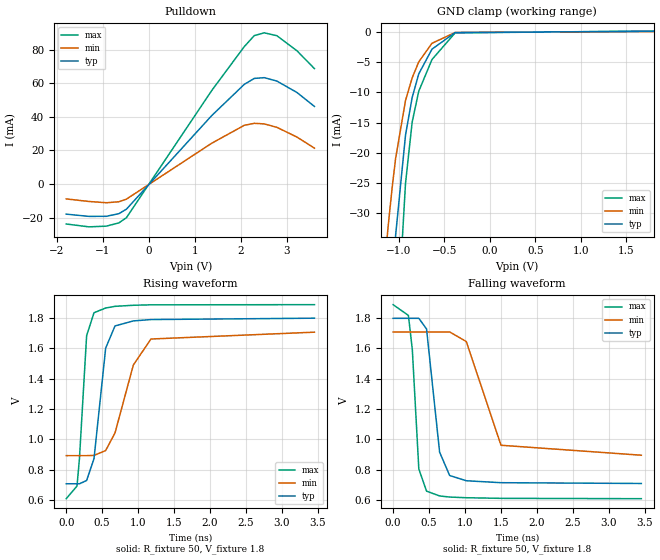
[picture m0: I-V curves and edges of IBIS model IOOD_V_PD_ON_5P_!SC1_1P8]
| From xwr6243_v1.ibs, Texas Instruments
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|   Model Cell IOOD_V_PD_ON_5P_!SC1_1P8
|IOOD_V_PD_ON_5P_!SC1_1P8
[Model]   IOOD_V_PD_ON_5P_!SC1_1P8
Model_type   I/O_open_drain
Polarity   Non-Inverting
Enable   Active-Low
Vinl =  0.63
Vinh =  1.17
Cref =  15pF
Rref =  100.0000M
Vref =  0V
Vmeas =  0.9
|   typ   min   max
C_comp   2.233931p   2.204415p   2.290246p
[Model Spec]
Vinl   0.63   0.5985   0.6615
Vinh   1.17   1.1115   1.2285
[Temperature Range]   25   125   -40
[Voltage Range]   1.8   1.71   1.89
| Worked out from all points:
|   slope of the pulldown table from 0 to 0.27 V, typ, clamps not added: 32.2 ohm
|   GND clamp passes 1 mA (typ) near -0.53 V on its own axis
|   rising waveform, R_fixture 50, V_fixture 1.8: 20-80 % time 141ps typ, 294ps min, 91.5ps max; typ from 0.708 V to 1.8 V
|   falling waveform, R_fixture 50, V_fixture 1.8: 20-80 % time 128ps typ, 263ps min, 86.2ps max; typ from 1.8 V to 0.709 V
| Where Nom  PVT is Nominal Process, 1.8V, 25C
|   Fast PVT is Strong Process,  1.89V, -40C
|   Slow PVT is Weak Process,   1.71V, 125C
[Pulldown]
|   voltage   I(typ)   I(min)   I(max)
-1.8V     -17.92mA   -8.85mA    -23.8mA
-1.309V   -19.26mA   -10.37mA   -25.5mA
-927.3mV  -19.22mA   -11.12mA   -25.08mA
-654.5mV  -17.65mA   -10.56mA   -23.13mA
-490.9mV  -14.97mA   -8.985mA   -20.05mA
1.364V    40.78mA    24.32mA    55.69mA
2.073V    59.4mA     35mA       81.9mA
2.291V    62.96mA    36.2mA     88.48mA
2.509V    63.41mA    35.84mA    90.12mA
2.782V    61.38mA    33.82mA    88.42mA
3.218V    54.59mA    28.02mA    79.45mA
3.6V      46.26mA    21.39mA    68.79mA
[GND_clamp]
|   voltage   I(typ)   I(min)   I(max)
-1.8V     -270.2mA   -170.2mA   -430.1mA
-1.255V   -91.66mA   -55.91mA   -148.4mA
-1.145V   -59.91mA   -36.45mA   -97.1mA
-1.109V   -50.48mA   -30.83mA   -81.56mA
-1.073V   -41.73mA   -25.65mA   -67.06mA
-1.036V   -33.67mA   -20.93mA   -53.6mA
-927.3mV  -17.08mA   -11.35mA   -25.06mA
-854.5mV  -10.88mA   -7.624mA   -14.94mA
-781.8mV  -6.944mA   -4.956mA   -9.81mA
-636.4mV  -2.852mA   -1.883mA   -4.567mA
-381.8mV  -107.5uA   -92.09uA   -158.2uA
1.8V      101.9uA    59.12uA    150.8uA
[Ramp]
| variable   typ   min   max
dV/dt_f 0.66510514/0.13039257n 0.49951363/0.26900827n 0.77657515/87.836977p
dV/dt_r 0.66379743/0.17656601n 0.50939443/0.36426095n 0.78039524/0.10503855n
R_load = 50
[Rising Waveform]
R_fixture = 50
V_fixture = 1.8
V_fixture_min = 1.71
V_fixture_max = 1.89
|   time   V(typ)   V(min)   V(max)
0s        708.5mV    893.6mV    610.3mV
149.8ps   708.5mV    893.6mV    693.4mV
183.7ps   708.5mV    893.6mV    873.7mV
283.5ps   729.6mV    893.6mV    1.683V
386.4ps   874.1mV    894.9mV    1.834V
548.5ps   1.601V     927.1mV    1.865V
678.4ps   1.747V     1.043V     1.876V
933.5ps   1.78V      1.49V      1.883V
1.179ns   1.789V     1.661V     1.886V
3.453ns   1.798V     1.706V     1.887V
[Falling Waveform]
R_fixture = 50
V_fixture = 1.8
V_fixture_min = 1.71
V_fixture_max = 1.89
|   time   V(typ)   V(min)   V(max)
0s        1.798V     1.708V     1.888V
212.8ps   1.798V     1.708V     1.817V
267.2ps   1.798V     1.708V     1.592V
357.7ps   1.798V     1.708V     804.9mV
465ps     1.728V     1.708V     658.8mV
646.9ps   915.8mV    1.708V     627.2mV
786.7ps   761.8mV    1.708V     619.9mV
1.018ns   727.3mV    1.645V     615.4mV
1.501ns   714.5mV    961.2mV    611.3mV
3.453ns   709.3mV    895.6mV    609.1mV
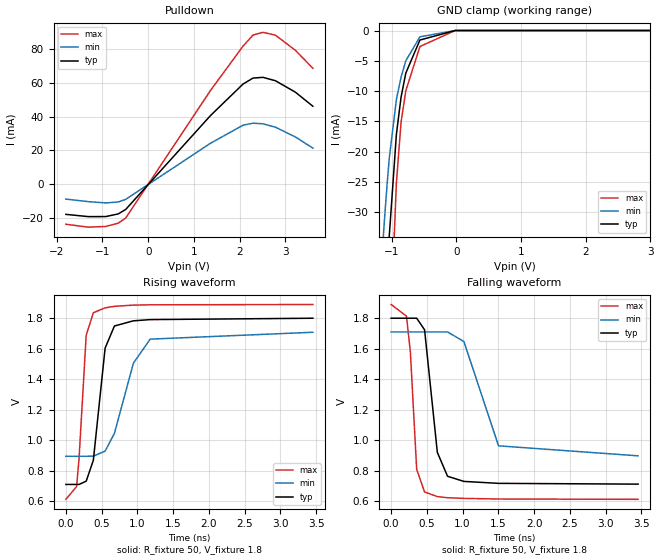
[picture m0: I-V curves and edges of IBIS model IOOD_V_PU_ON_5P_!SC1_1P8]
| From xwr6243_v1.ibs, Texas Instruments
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|   Model Cell IOOD_V_PU_ON_5P_!SC1_1P8
|IOOD_V_PU_ON_5P_!SC1_1P8
[Model]   IOOD_V_PU_ON_5P_!SC1_1P8
Model_type   I/O_open_drain
Polarity   Non-Inverting
Enable   Active-Low
Vinl =  0.63
Vinh =  1.17
Cref =  15pF
Rref =  100.0000M
Vref =  0V
Vmeas =  0.9
|   typ   min   max
C_comp   2.233931p   2.204415p   2.290246p
[Model Spec]
Vinl   0.63   0.5985   0.6615
Vinh   1.17   1.1115   1.2285
[Temperature Range]   25   125   -40
[Voltage Range]   1.8   1.71   1.89
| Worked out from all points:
|   slope of the pulldown table from 0 to 0.27 V, typ, clamps not added: 32.2 ohm
|   GND clamp passes 1 mA (typ) near -0.52 V on its own axis
|   rising waveform, R_fixture 50, V_fixture 1.8: 20-80 % time 141ps typ, 293ps min, 91.4ps max; typ from 0.711 V to 1.8 V
|   falling waveform, R_fixture 50, V_fixture 1.8: 20-80 % time 128ps typ, 263ps min, 86.1ps max; typ from 1.8 V to 0.711 V
| Where Nom  PVT is Nominal Process, 1.8V, 25C
|   Fast PVT is Strong Process,  1.89V, -40C
|   Slow PVT is Weak Process,   1.71V, 125C
[Pulldown]
|   voltage   I(typ)   I(min)   I(max)
-1.8V     -17.92mA   -8.85mA    -23.8mA
-1.309V   -19.26mA   -10.37mA   -25.51mA
-927.3mV  -19.22mA   -11.12mA   -25.08mA
-654.5mV  -17.65mA   -10.56mA   -23.13mA
-490.9mV  -14.97mA   -8.985mA   -20.05mA
1.364V    40.78mA    24.32mA    55.7mA
2.073V    59.41mA    35mA       81.9mA
2.291V    62.96mA    36.2mA     88.48mA
2.509V    63.41mA    35.84mA    90.12mA
2.782V    61.38mA    33.82mA    88.42mA
3.218V    54.59mA    28.02mA    79.45mA
3.6V      46.26mA    21.39mA    68.79mA
[GND_clamp]
|   voltage   I(typ)   I(min)   I(max)
-1.8V     -270.2mA   -170.2mA   -430.1mA
-1.255V   -91.68mA   -55.92mA   -148.5mA
-1.145V   -59.94mA   -36.46mA   -97.14mA
-1.109V   -50.51mA   -30.84mA   -81.61mA
-1.073V   -41.77mA   -25.67mA   -67.13mA
-1.036V   -33.71mA   -20.95mA   -53.68mA
-927.3mV  -17.15mA   -11.38mA   -25.19mA
-854.5mV  -10.96mA   -7.663mA   -15.08mA
-781.8mV  -7.031mA   -5.001mA   -9.947mA
-563.6mV  -1.569mA   -1.041mA   -2.641mA
-18.18mV  0A         0A         0A
3.6V      0A         0A         0A
[Ramp]
| variable   typ   min   max
dV/dt_f 0.66507934/0.13047563n 0.49947306/0.26909371n 0.77654614/87.861951p
dV/dt_r 0.66370141/0.17654672n 0.50912868/0.36419589n 0.78039356/0.10498627n
R_load = 50
[Rising Waveform]
R_fixture = 50
V_fixture = 1.8
V_fixture_min = 1.71
V_fixture_max = 1.89
|   time   V(typ)   V(min)   V(max)
0s        710.6mV    895.2mV    613mV
149.8ps   710.6mV    895.2mV    696.6mV
183.7ps   710.6mV    895.2mV    877.5mV
284.2ps   732.1mV    895.2mV    1.689V
384.1ps   869.5mV    896.4mV    1.836V
548.5ps   1.604V     928.8mV    1.868V
678.4ps   1.749V     1.045V     1.878V
943.6ps   1.783V     1.505V     1.886V
1.179ns   1.791V     1.663V     1.888V
3.453ns   1.8V       1.708V     1.89V
[Falling Waveform]
R_fixture = 50
V_fixture = 1.8
V_fixture_min = 1.71
V_fixture_max = 1.89
|   time   V(typ)   V(min)   V(max)
0s        1.8V       1.71V      1.89V
215ps     1.8V       1.71V      1.814V
269.6ps   1.8V       1.71V      1.578V
357.6ps   1.8V       1.71V      808.4mV
468ps     1.724V     1.71V      660.2mV
646.5ps   919.7mV    1.71V      629.7mV
789.1ps   763.1mV    1.71V      622.3mV
1.018ns   729.3mV    1.647V     617.9mV
1.502ns   716.5mV    962.7mV    613.8mV
3.453ns   711.4mV    897.1mV    611.7mV
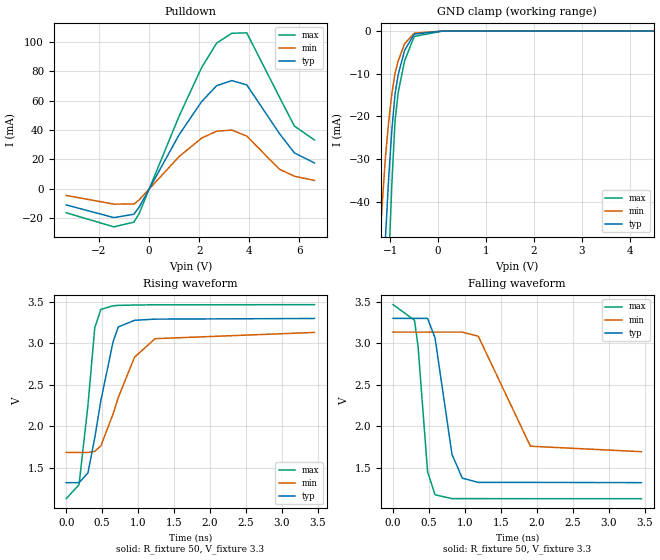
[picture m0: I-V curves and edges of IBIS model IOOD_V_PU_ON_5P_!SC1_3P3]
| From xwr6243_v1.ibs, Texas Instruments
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|   Model Cell IOOD_V_PU_ON_5P_!SC1_3P3
|IOOD_V_PU_ON_5P_!SC1_3P3
[Model]   IOOD_V_PU_ON_5P_!SC1_3P3
Model_type   I/O_open_drain
Polarity   Non-Inverting
Enable   Active-Low
Vinl =  0.8V
Vinh =  2V
Cref =  15pF
Rref =  100.0000M
Vref =  0V
Vmeas =  1.65
|   typ   min   max
C_comp   2.059994p   1.862014p   2.067327p
[Model Spec]
Vinl   0.8V   0.8V   0.8V
Vinh   2V   2V   2V
[Temperature Range]   25   125   -40
[Voltage Range]   3.3   3.135   3.465
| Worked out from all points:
|   slope of the pulldown table from 0 to 0.495 V, typ, clamps not added: 31.8 ohm
|   GND clamp passes 1 mA (typ) near -0.52 V on its own axis
|   rising waveform, R_fixture 50, V_fixture 3.3: 20-80 % time 251ps typ, 370ps min, 151ps max; typ from 1.32 V to 3.3 V
|   falling waveform, R_fixture 50, V_fixture 3.3: 20-80 % time 196ps typ, 407ps min, 120ps max; typ from 3.3 V to 1.32 V
| Where Nom  PVT is Nominal Process, 3.3V, 25C
|   Fast PVT is Strong Process,  3.465V, -40C
|   Slow PVT is Weak Process,   3.135V, 125C
[Pulldown]
|   voltage   I(typ)   I(min)   I(max)
-3.3V     -10.92mA   -4.469mA   -16.24mA
-1.4V     -19.52mA   -10.37mA   -25.81mA
-600mV    -17.22mA   -10.34mA   -22.6mA
-400mV    -12.67mA   -7.623mA   -17.05mA
1.2V      36.7mA     21.92mA    49.35mA
2.1V      59.3mA     34.49mA    82.4mA
2.7V      70.09mA    39.15mA    99.03mA
3.3V      73.56mA    39.95mA    105.7mA
3.9V      70.66mA    35.84mA    106mA
5.2V      37.64mA    13.39mA    62.46mA
5.8V      24.43mA    8.578mA    42.66mA
6.6V      17.6mA     5.765mA    33.17mA
[GND_clamp]
|   voltage   I(typ)   I(min)   I(max)
-3.3V     -787.2mA   -627.7mA   -1.235A
-1.233V   -85.67mA   -52.14mA   -138.8mA
-1.167V   -66.48mA   -40.37mA   -107.8mA
-1.1V     -48.26mA   -29.38mA   -78.01mA
-1.033V   -34.3mA    -21.2mA    -54.61mA
-966.7mV  -23.1mA    -14.68mA   -35.59mA
-900mV    -14.66mA   -9.807mA   -20.94mA
-833.3mV  -10.12mA   -6.96mA    -14.29mA
-700mV    -4.501mA   -2.971mA   -6.963mA
-500mV    -717.7uA   -493.4uA   -1.261mA
100mV     0A         0A         0A
6.6V      0A         0A         0A
[Ramp]
| variable   typ   min   max
dV/dt_f  1.1950495/0.19765753n 0.88964479/0.4200289n  1.4061684/0.12033881n
dV/dt_r  1.1911245/0.23430808n 0.88879161/0.46777455n  1.4196341/0.14133941n
R_load = 50
[Rising Waveform]
R_fixture = 50
V_fixture = 3.3
V_fixture_min = 3.135
V_fixture_max = 3.465
|   time   V(typ)   V(min)   V(max)
0s        1.324V     1.688V     1.132V
178.2ps   1.325V     1.688V     1.3V
302ps     1.441V     1.688V     2.255V
397.2ps   1.866V     1.701V     3.188V
481.7ps   2.312V     1.767V     3.408V
652.6ps   3.023V     2.153V     3.452V
724.3ps   3.197V     2.349V     3.456V
949.9ps   3.277V     2.833V     3.461V
1.235ns   3.291V     3.056V     3.463V
3.453ns   3.299V     3.131V     3.465V
[Falling Waveform]
R_fixture = 50
V_fixture = 3.3
V_fixture_min = 3.135
V_fixture_max = 3.465
|   time   V(typ)   V(min)   V(max)
0s        3.299V     3.134V     3.464V
297.1ps   3.299V     3.134V     3.277V
347.5ps   3.299V     3.134V     2.96V
479.3ps   3.299V     3.134V     1.457V
583.2ps   3.064V     3.134V     1.178V
818.9ps   1.664V     3.134V     1.132V
962ps     1.378V     3.134V     1.132V
1.185ns   1.327V     3.084V     1.132V
1.91ns    1.327V     1.762V     1.131V
3.453ns   1.324V     1.696V     1.131V
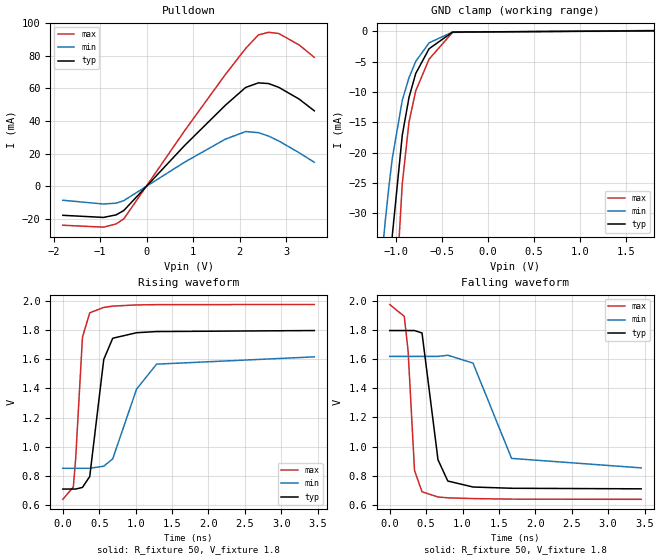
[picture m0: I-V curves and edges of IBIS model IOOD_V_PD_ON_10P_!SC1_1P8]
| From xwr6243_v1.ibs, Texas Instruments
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|   Model Cell IOOD_V_PD_ON_10P_!SC1_1P8
|IOOD_V_PD_ON_10P_!SC1_1P8
[Model]   IOOD_V_PD_ON_10P_!SC1_1P8
Model_type   I/O_open_drain
Polarity   Non-Inverting
Enable   Active-Low
Vinl =  0.63
Vinh =  1.17
Cref =  15pF
Rref =  100.0000M
Vref =  0V
Vmeas =  0.9
|   typ   min   max
C_comp   2.290246p   2.205796p   2.292736p
[Model Spec]
Vinl   0.63   0.567   0.693
Vinh   1.17   1.053   1.287
[Temperature Range]   25   125   -40
[Voltage Range]   1.8   1.62   1.98
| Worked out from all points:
|   slope of the pulldown table from 0 to 0.27 V, typ, clamps not added: 32.2 ohm
|   GND clamp passes 1 mA (typ) near -0.53 V on its own axis
|   rising waveform, R_fixture 50, V_fixture 1.8: 20-80 % time 141ps typ, 321ps min, 87.4ps max; typ from 0.709 V to 1.8 V
|   falling waveform, R_fixture 50, V_fixture 1.8: 20-80 % time 128ps typ, 291ps min, 84ps max; typ from 1.8 V to 0.709 V
| Where Nom  PVT is Nominal Process, 1.8V, 25C
|   Fast PVT is Strong Process,  1.98V, -40C
|   Slow PVT is Weak Process,   1.62V, 125C
[Pulldown]
|   voltage   I(typ)   I(min)   I(max)
-1.8V     -17.92mA   -8.674mA   -24.03mA
-927.3mV  -19.22mA   -10.99mA   -25.2mA
-654.5mV  -17.65mA   -10.46mA   -23.22mA
-490.9mV  -14.97mA   -8.904mA   -20.12mA
818.2mV   25.05mA    14.78mA    34.16mA
1.691V    49.7mA     28.87mA    68.58mA
2.127V    60.63mA    33.53mA    84.59mA
2.4V      63.43mA    32.85mA    92.9mA
2.618V    62.99mA    30.74mA    94.47mA
2.836V    60.69mA    27.76mA    93.76mA
3.273V    53.49mA    20.53mA    86.73mA
3.6V      46.26mA    14.64mA    79.12mA
[GND_clamp]
|   voltage   I(typ)   I(min)   I(max)
-1.8V     -270.2mA   -170.2mA   -430.1mA
-1.255V   -91.66mA   -55.91mA   -148.4mA
-1.145V   -59.91mA   -36.45mA   -97.1mA
-1.109V   -50.48mA   -30.83mA   -81.56mA
-1.073V   -41.73mA   -25.65mA   -67.06mA
-1.036V   -33.67mA   -20.93mA   -53.6mA
-927.3mV  -17.08mA   -11.35mA   -25.06mA
-854.5mV  -10.88mA   -7.623mA   -14.95mA
-781.8mV  -6.944mA   -4.955mA   -9.81mA
-636.4mV  -2.852mA   -1.883mA   -4.568mA
-381.8mV  -107.5uA   -91.83uA   -158.4uA
1.8V      101.9uA    59.86uA    152.6uA
[Ramp]
| variable   typ   min   max
dV/dt_f 0.66510519/0.13032151n 0.47058165/0.29690499n 0.81401058/85.695381p
dV/dt_r 0.66379761/0.17655114n 0.48092033/0.39577716n 0.81801831/99.528337p
R_load = 50
[Rising Waveform]
R_fixture = 50
V_fixture = 1.8
V_fixture_min = 1.62
V_fixture_max = 1.98
|   time   V(typ)   V(min)   V(max)
0s        708.5mV    851.3mV    637.8mV
143.7ps   708.5mV    851.3mV    722.4mV
176.4ps   708.5mV    851.3mV    920mV
269.4ps   719.8mV    851.3mV    1.753V
369.4ps   794.8mV    851.3mV    1.92V
561.6ps   1.599V     865.5mV    1.957V
684.8ps   1.745V     916mV      1.966V
1.012ns   1.783V     1.395V     1.974V
1.287ns   1.791V     1.567V     1.976V
3.453ns   1.798V     1.617V     1.977V
[Falling Waveform]
R_fixture = 50
V_fixture = 1.8
V_fixture_min = 1.62
V_fixture_max = 1.98
|   time   V(typ)   V(min)   V(max)
0s        1.798V     1.62V      1.977V
200.1ps   1.798V     1.62V      1.895V
252.3ps   1.798V     1.62V      1.658V
340.4ps   1.798V     1.62V      835.7mV
443.5ps   1.781V     1.62V      689.1mV
663.1ps   908.8mV    1.62V      653.2mV
797.3ps   763mV      1.628V     647.2mV
1.144ns   721.8mV    1.574V     642.3mV
1.673ns   713.2mV    918.6mV    638.4mV
3.453ns   709.3mV    853.4mV    637.1mV
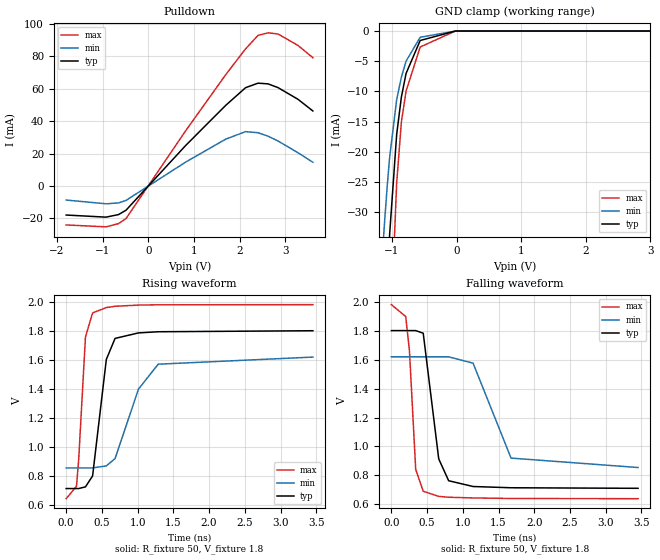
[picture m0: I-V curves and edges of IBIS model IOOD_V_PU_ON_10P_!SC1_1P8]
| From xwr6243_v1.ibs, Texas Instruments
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|   Model Cell IOOD_V_PU_ON_10P_!SC1_1P8
|IOOD_V_PU_ON_10P_!SC1_1P8
[Model]   IOOD_V_PU_ON_10P_!SC1_1P8
Model_type   I/O_open_drain
Polarity   Non-Inverting
Enable   Active-Low
Vinl =  0.63
Vinh =  1.17
Cref =  15pF
Rref =  100.0000M
Vref =  0V
Vmeas =  0.9
|   typ   min   max
C_comp   2.290246p   2.205796p   2.292736p
[Model Spec]
Vinl   0.63   0.567   0.693
Vinh   1.17   1.053   1.287
[Temperature Range]   25   125   -40
[Voltage Range]   1.8   1.62   1.98
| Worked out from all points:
|   slope of the pulldown table from 0 to 0.27 V, typ, clamps not added: 32.2 ohm
|   GND clamp passes 1 mA (typ) near -0.52 V on its own axis
|   rising waveform, R_fixture 50, V_fixture 1.8: 20-80 % time 141ps typ, 321ps min, 87.2ps max; typ from 0.71 V to 1.8 V
|   falling waveform, R_fixture 50, V_fixture 1.8: 20-80 % time 128ps typ, 290ps min, 84ps max; typ from 1.8 V to 0.711 V
| Where Nom  PVT is Nominal Process, 1.8V, 25C
|   Fast PVT is Strong Process,  1.98V, -40C
|   Slow PVT is Weak Process,   1.62V, 125C
[Pulldown]
|   voltage   I(typ)   I(min)   I(max)
-1.8V     -17.92mA   -8.674mA   -24.03mA
-927.3mV  -19.22mA   -10.99mA   -25.21mA
-654.5mV  -17.65mA   -10.46mA   -23.22mA
-490.9mV  -14.97mA   -8.904mA   -20.12mA
818.2mV   25.06mA    14.78mA    34.16mA
1.691V    49.7mA     28.87mA    68.59mA
2.127V    60.63mA    33.53mA    84.59mA
2.4V      63.43mA    32.84mA    92.9mA
2.618V    62.99mA    30.74mA    94.47mA
2.836V    60.69mA    27.76mA    93.76mA
3.273V    53.49mA    20.53mA    86.73mA
3.6V      46.26mA    14.64mA    79.11mA
[GND_clamp]
|   voltage   I(typ)   I(min)   I(max)
-1.8V     -270.2mA   -170.2mA   -430.1mA
-1.255V   -91.68mA   -55.92mA   -148.5mA
-1.145V   -59.94mA   -36.46mA   -97.15mA
-1.109V   -50.51mA   -30.84mA   -81.62mA
-1.073V   -41.77mA   -25.67mA   -67.14mA
-1.036V   -33.71mA   -20.94mA   -53.69mA
-927.3mV  -17.15mA   -11.38mA   -25.2mA
-854.5mV  -10.96mA   -7.657mA   -15.09mA
-781.8mV  -7.031mA   -4.995mA   -9.958mA
-563.6mV  -1.569mA   -1.036mA   -2.651mA
-18.18mV  0A         0A         0A
3.6V      0A         0A         0A
[Ramp]
| variable   typ   min   max
dV/dt_f  0.6650793/0.13041675n 0.47054236/0.29704481n 0.81398134/85.756989p
dV/dt_r 0.66369803/0.17655946n 0.48061665/0.39565974n 0.81803201/99.446129p
R_load = 50
[Rising Waveform]
R_fixture = 50
V_fixture = 1.8
V_fixture_min = 1.62
V_fixture_max = 1.98
|   time   V(typ)   V(min)   V(max)
0s        710.4mV    852.8mV    640.4mV
144.3ps   710.4mV    852.8mV    725.7mV
175.6ps   710.4mV    852.8mV    911.9mV
270.1ps   722mV      852.8mV    1.757V
370ps     797.4mV    852.8mV    1.923V
562.2ps   1.602V     867mV      1.96V
684.5ps   1.747V     917.1mV    1.969V
1.012ns   1.785V     1.397V     1.977V
1.288ns   1.793V     1.569V     1.979V
3.453ns   1.8V       1.618V     1.98V
[Falling Waveform]
R_fixture = 50
V_fixture = 1.8
V_fixture_min = 1.62
V_fixture_max = 1.98
|   time   V(typ)   V(min)   V(max)
0s        1.8V       1.619V     1.979V
200.7ps   1.8V       1.619V     1.897V
252.9ps   1.8V       1.619V     1.661V
340.6ps   1.8V       1.619V     841.1mV
445.7ps   1.782V     1.619V     691.1mV
662.6ps   914.6mV    1.619V     655.8mV
801.7ps   763.7mV    1.619V     649.7mV
1.144ns   723.8mV    1.575V     644.9mV
1.675ns   715.2mV    919.9mV    641.1mV
3.453ns   711.4mV    854.9mV    639.8mV
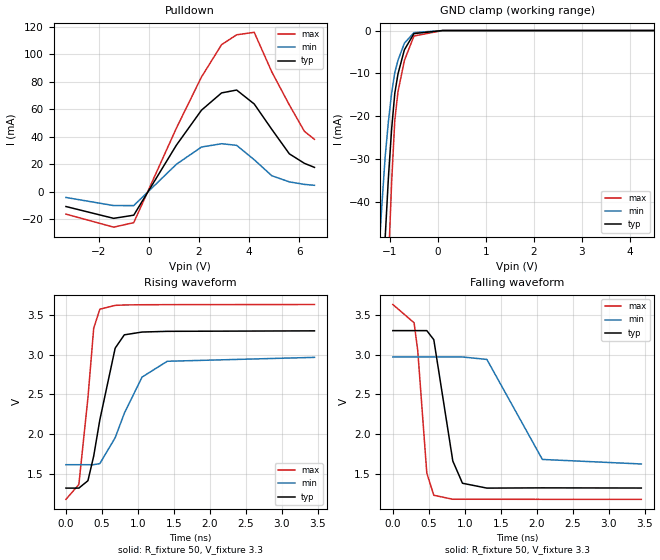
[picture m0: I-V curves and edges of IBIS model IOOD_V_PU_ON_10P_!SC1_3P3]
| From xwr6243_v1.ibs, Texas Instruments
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|   Model Cell IOOD_V_PU_ON_10P_!SC1_3P3
|IOOD_V_PU_ON_10P_!SC1_3P3
[Model]   IOOD_V_PU_ON_10P_!SC1_3P3
Model_type   I/O_open_drain
Polarity   Non-Inverting
Enable   Active-Low
Vinl =  0.8V
Vinh =  2V
Cref =  15pF
Rref =  100.0000M
Vref =  0V
Vmeas =  1.65
|   typ   min   max
C_comp   2.059994p   1.912853p   2.135747p
[Model Spec]
Vinl   0.8V   0.8V   0.8V
Vinh   2V   2V   2V
[Temperature Range]   25   125   -40
[Voltage Range]   3.3   2.97   3.63
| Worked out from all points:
|   slope of the pulldown table from 0 to 0.495 V, typ, clamps not added: 31.8 ohm
|   GND clamp passes 1 mA (typ) near -0.52 V on its own axis
|   rising waveform, R_fixture 50, V_fixture 3.3: 20-80 % time 251ps typ, 384ps min, 142ps max; typ from 1.32 V to 3.3 V
|   falling waveform, R_fixture 50, V_fixture 3.3: 20-80 % time 196ps typ, 423ps min, 118ps max; typ from 3.3 V to 1.32 V
| Where Nom  PVT is Nominal Process, 3.3V, 25C
|   Fast PVT is Strong Process,  3.63V, -40C
|   Slow PVT is Weak Process,   2.97V, 125C
[Pulldown]
|   voltage   I(typ)   I(min)   I(max)
-3.3V     -10.92mA   -4.307mA   -16.45mA
-1.4V     -19.52mA   -10.22mA   -25.94mA
-600mV    -17.22mA   -10.25mA   -22.66mA
1.1V      33.8mA     19.88mA    46.22mA
2.1V      59.3mA     32.44mA    83.48mA
2.9V      71.86mA    34.84mA    107mA
3.5V      73.95mA    33.66mA    114.2mA
4.2V      63.8mA     23.19mA    116mA
4.9V      45.33mA    11.53mA    87.2mA
5.6V      27.47mA    7.046mA    63.1mA
6.2V      20.56mA    5.221mA    43.87mA
6.6V      17.6mA     4.555mA    38.05mA
[GND_clamp]
|   voltage   I(typ)   I(min)   I(max)
-3.3V     -787.2mA   -607.8mA   -1.235A
-1.233V   -85.67mA   -52.14mA   -138.8mA
-1.167V   -66.48mA   -40.37mA   -107.8mA
-1.1V     -48.26mA   -29.37mA   -78.02mA
-1.033V   -34.3mA    -21.2mA    -54.63mA
-966.7mV  -23.1mA    -14.67mA   -35.61mA
-900mV    -14.66mA   -9.802mA   -20.96mA
-833.3mV  -10.12mA   -6.954mA   -14.3mA
-700mV    -4.501mA   -2.964mA   -6.982mA
-500mV    -717.7uA   -486.4uA   -1.28mA
100mV     0A         0A         0A
6.6V      0A         0A         0A
[Ramp]
| variable   typ   min   max
dV/dt_f  1.1950496/0.19764937n 0.83550004/0.43952187n  1.4746494/0.11842933n
dV/dt_r  1.1911253/0.23433637n 0.82860168/0.48872151n  1.4896931/0.13693182n
R_load = 50
[Rising Waveform]
R_fixture = 50
V_fixture = 3.3
V_fixture_min = 2.97
V_fixture_max = 3.63
|   time   V(typ)   V(min)   V(max)
0s        1.324V     1.618V     1.183V
179.3ps   1.324V     1.618V     1.369V
305.5ps   1.417V     1.618V     2.459V
385.5ps   1.726V     1.618V     3.332V
470.7ps   2.181V     1.632V     3.571V
684ps     3.082V     1.957V     3.619V
810.8ps   3.249V     2.263V     3.624V
1.057ns   3.284V     2.718V     3.627V
1.408ns   3.293V     2.917V     3.628V
3.453ns   3.299V     2.966V     3.63V
[Falling Waveform]
R_fixture = 50
V_fixture = 3.3
V_fixture_min = 2.97
V_fixture_max = 3.63
|   time   V(typ)   V(min)   V(max)
0s        3.301V     2.97V      3.629V
295.6ps   3.301V     2.97V      3.399V
346.7ps   3.301V     2.97V      3.046V
472.1ps   3.301V     2.97V      1.511V
569.4ps   3.187V     2.97V      1.233V
833.3ps   1.664V     2.97V      1.183V
967.6ps   1.384V     2.97V      1.183V
1.307ns   1.323V     2.939V     1.183V
2.078ns   1.326V     1.683V     1.182V
3.453ns   1.324V     1.626V     1.182V
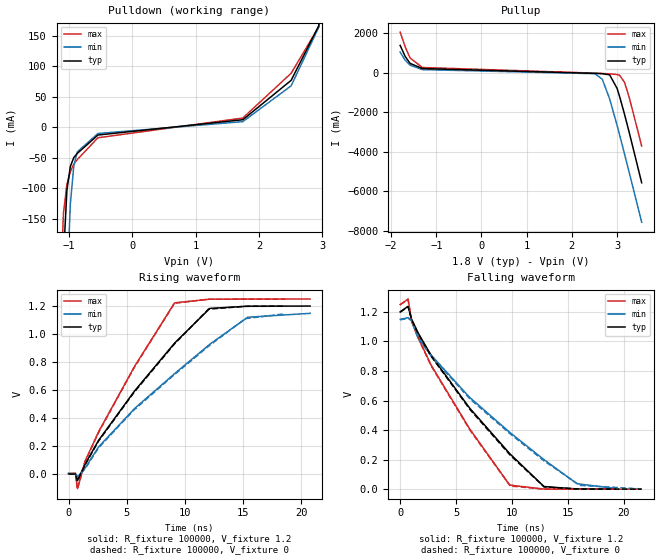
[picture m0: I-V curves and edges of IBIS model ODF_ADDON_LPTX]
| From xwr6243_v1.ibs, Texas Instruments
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|   Model Cell ODF_ADDON_LPTX
[Model]   ODF_ADDON_LPTX
Model_type   Output
Polarity   Non-Inverting
Cref =  15.0000pF
Rref =  100.0000M
Vref =  0V
Vmeas =  0.6
|   typ   min   max
C_comp   2p   1.8p   2.2p
[Temperature Range]   25   125   -40
[Voltage Range]   1.8   1.62   1.98
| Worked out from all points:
|   slope of the pulldown table from 0 to 0.27 V, typ, clamps not added: 170 ohm
|   slope of the pullup table from 0 to 0.27 V, typ, clamps not added: 26.1 ohm
|   rising waveform, R_fixture 100000, V_fixture 1.2: 20-80 % time 6.77ns typ, 9.06ns min, 5.05ns max; typ from 0.002 V to 1.2 V
|   rising waveform, R_fixture 100000, V_fixture 0: 20-80 % time 6.79ns typ, 9.07ns min, 5.06ns max; typ from 0 V to 1.2 V
|   falling waveform, R_fixture 100000, V_fixture 1.2: 20-80 % time 7.46ns typ, 9.67ns min, 5.88ns max; typ from 1.2 V to 0 V
|   falling waveform, R_fixture 100000, V_fixture 0: 20-80 % time 7.41ns typ, 9.62ns min, 5.85ns max; typ from 1.2 V to 0 V
| Where Nom  PVT is Nominal Process, 1.8V, 25C
|   Fast PVT is Strong Process,  1.98V, -40C
|   Slow PVT is Weak Process,   1.62V, 125C
[Pulldown]
|   voltage   I(typ)   I(min)   I(max)
-1.8V     -6.084A    -6.434A    -5.928A
-1.145V   -450.3mA   -825mA     -286.9mA
-1.091V   -216.2mA   -504.4mA   -141.5mA
-1.036V   -103.7mA   -266.7mA   -93.67mA
-981.8mV  -64.47mA   -126.7mA   -72.92mA
-927.3mV  -49.86mA   -63.99mA   -60.38mA
-872.7mV  -43.11mA   -40.65mA   -53.25mA
-545.5mV  -12.93mA   -10.42mA   -17.42mA
1.745V    12.14mA    9.001mA    14.92mA
2.509V    76.63mA    67.66mA    88.25mA
2.945V    165.9mA    163.5mA    164.1mA
3.545V    1.094A     1.691A     693mA
[Pullup]
|   voltage   I(typ)   I(min)   I(max)
-1.8V     1.387A     1.05A      2.064A
-1.691V   838mA      645.5mA    1.326A
-1.582V   479.1mA    387.9mA    753.7mA
-1.309V   214.3mA    161.5mA    269.5mA
2.509V    -29.06mA   -45.03mA   -17.59mA
2.673V    -43.83mA   -325.4mA   -36.02mA
2.836V    -103.1mA   -1.322A    -53.23mA
3V        -787.3mA   -2.656A    -87.17mA
3.055V    -1.189A    -3.13A     -122mA
3.164V    -2.091A    -4.103A    -478.1mA
3.273V    -3.057A    -5.094A    -1.274A
3.545V    -5.576A    -7.574A    -3.716A
[Ramp]
| variable   typ   min   max
dV/dt_f  0.6691031/13.80777n   0.4177219/14.04618n   0.8456401/12.02406n
dV/dt_r  0.5520643/10.90207n   0.4057285/13.50742n   0.6458394/8.383141n
R_load = 50
[Rising Waveform]
R_fixture = 100000
V_fixture = 1.2
V_fixture_min = 1.15
V_fixture_max = 1.25
|   time   V(typ)   V(min)   V(max)
0s        2.025mV    3.196mV    1.57mV
580ps     -103.8uV   2.422mV    6.287mV
765ps     -47.93mV   -22.11mV   -105.7mV
1.43ns    71.59mV    43.91mV    93.93mV
2.575ns   239.8mV    193mV      300.8mV
5.675ns   593.6mV    468.2mV    770.1mV
9.11ns    935.5mV    717.1mV    1.223V
12.13ns   1.183V     927mV      1.249V
15.39ns   1.199V     1.12V      1.25V
20.75ns   1.2V       1.148V     1.25V
[Rising Waveform]
R_fixture = 100000
V_fixture = 0
V_fixture_min = 0
V_fixture_max = 0
|   time   V(typ)   V(min)   V(max)
0s        4.07uV     30.52uV    9.664uV
590ps     -3.025mV   -1.565mV   3.591mV
760ps     -50.31mV   -25.41mV   -109.1mV
1.41ns    64.26mV    35.66mV    85.91mV
2.55ns    232.1mV    184.1mV    292.3mV
5.59ns    579.6mV    455mV      753.6mV
9.095ns   929mV      709.8mV    1.22V
12.02ns   1.178V     913mV      1.249V
15.19ns   1.198V     1.11V      1.249V
18.61ns   1.199V     1.145V     1.25V
[Falling Waveform]
R_fixture = 100000
V_fixture = 1.2
V_fixture_min = 1.15
V_fixture_max = 1.25
|   time   V(typ)   V(min)   V(max)
0s        1.2V       1.15V      1.25V
710ps     1.238V     1.161V     1.287V
1.02ns    1.151V     1.143V     1.139V
1.595ns   1.059V     1.03V      1.029V
2.775ns   905.1mV    907.6mV    838.9mV
6.21ns    549.5mV    621.9mV    409mV
9.8ns     240.8mV    385.3mV    27.93mV
12.87ns   17.87mV    200mV      588.5uV
15.82ns   1.351mV    37mV       289uV
19.26ns   462.2uV    4.824mV    232.1uV
[Falling Waveform]
R_fixture = 100000
V_fixture = 0
V_fixture_min = 0
V_fixture_max = 0
|   time   V(typ)   V(min)   V(max)
0s        1.198V     1.146V     1.248V
710ps     1.236V     1.158V     1.285V
1.015ns   1.149V     1.14V      1.138V
1.6ns     1.054V     1.023V     1.024V
2.77ns    900mV      901.1mV    835mV
6.255ns   538.7mV    610.4mV    398.7mV
9.85ns    229.9mV    374.3mV    21.47mV
12.89ns   15.02mV    190.9mV    377.4uV
16.07ns   829.9uV    26.03mV    163.3uV
21.61ns   189.8uV    1.653mV    125.2uV
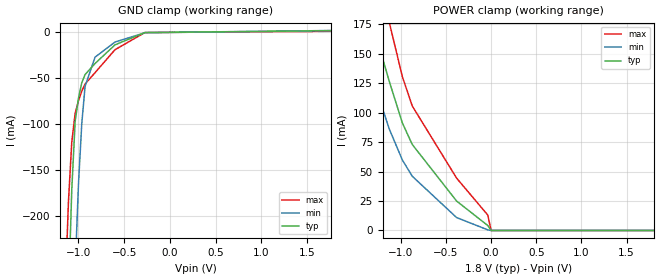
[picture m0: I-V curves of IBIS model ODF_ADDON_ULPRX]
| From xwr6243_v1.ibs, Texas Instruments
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|   Model Cell ODF_ADDON_ULPRX
[Model]   ODF_ADDON_ULPRX
Model_type   Input
Polarity   Non-Inverting
Vinl =  0.5
Vinh =  0.61
|   typ   min   max
C_comp   2p   1.8p   2.2p
[Model Spec]
Vinl   0.5   0.342   0.66
Vinh   0.61   0.382   0.838
[Temperature Range]   25   125   -40
[Voltage Range]   1.8   1.62   1.98
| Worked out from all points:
|   GND clamp passes 1 mA (typ) near -0.35 V on its own axis
|   POWER clamp passes 1 mA (typ) near -0.01 V on its own axis
| Where Nom  PVT is Nominal Process, 1.8V, 25C
|   Fast PVT is Strong Process,  1.98V, -40C
|   Slow PVT is Weak Process,   1.62V, 125C
[POWER_clamp]
|   voltage   I(typ)   I(min)   I(max)
-1.8V     1.381A     1.043A     2.062A
-1.4V     219.4mA    175.4mA    303.6mA
-1.364V   198.6mA    154.8mA    270.4mA
-1.309V   177.2mA    132.5mA    240.8mA
-1.255V   160.5mA    115.8mA    219.3mA
-1.127V   126.6mA    86.18mA    176.7mA
-981.8mV  91.26mA    59.79mA    130.5mA
-872.7mV  73.01mA    46.05mA    105.7mA
-381.8mV  24.98mA    10.97mA    44.44mA
-36.36mV  4.17mA     512.2uA    13.05mA
0V        0A         0A         0A
1.8V      0A         0A         0A
[GND_clamp]
|   voltage   I(typ)   I(min)   I(max)
-1.8V     -6.082A    -6.432A    -5.927A
-1.145V   -444.2mA   -819.4mA   -281.3mA
-1.109V   -287.4mA   -605mA     -184.1mA
-1.073V   -171.7mA   -418.3mA   -119.7mA
-1.036V   -97.09mA   -259.3mA   -88.27mA
-1V       -71.87mA   -166.3mA   -74.81mA
-963.6mV  -54.84mA   -99.48mA   -64.13mA
-927.3mV  -46mA      -58.73mA   -56.25mA
-818.2mV  -33.88mA   -26.95mA   -43.88mA
-600mV    -13.55mA   -10.48mA   -18.81mA
-272.7mV  -124.7uA   -376.2uA   -116.2uA
1.764V    1.931mA    2.089mA    1.23mA
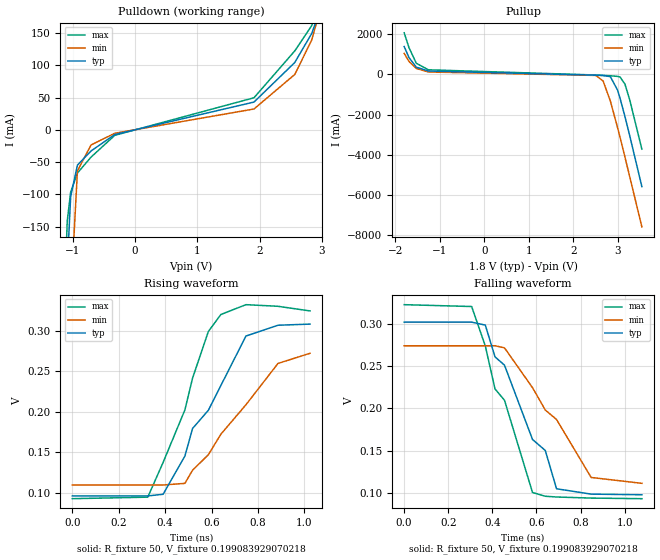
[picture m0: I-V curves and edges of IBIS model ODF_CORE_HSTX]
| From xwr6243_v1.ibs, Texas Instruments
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|   Model Cell ODF_CORE_HSTX
[Model]   ODF_CORE_HSTX
Model_type   Output
Polarity   Non-Inverting
Cref =  2.0000pF
Rref =  100.0000
Vref =  0V
Vmeas =  0.2
|   typ   min   max
C_comp   2p   1.8p   2.2p
[Temperature Range]   25   125   -40
[Voltage Range]   1.8   1.62   1.98
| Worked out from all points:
|   slope of the pulldown table from 0 to 0.27 V, typ, clamps not added: 47.5 ohm
|   slope of the pullup table from 0 to 0.27 V, typ, clamps not added: 85.5 ohm
|   rising waveform, R_fixture 50, V_fixture 0.199083929070218: 20-80 % time 224ps typ, 287ps min, 173ps max; typ from 0.097 V to 0.308 V
|   falling waveform, R_fixture 50, V_fixture 0.199083929070218: 20-80 % time 241ps typ, 294ps min, 191ps max; typ from 0.302 V to 0.098 V
| Where Nom  PVT is Nominal Process, 1.8V, 25C
|   Fast PVT is Strong Process,  1.98V, -40C
|   Slow PVT is Weak Process,   1.62V, 125C
[Pulldown]
|   voltage   I(typ)   I(min)   I(max)
-1.8V     -6.083A    -6.433A    -5.927A
-1.145V   -447.1mA   -820.9mA   -285.2mA
-1.091V   -213.6mA   -499.9mA   -141.8mA
-1.036V   -103.6mA   -262.3mA   -96.65mA
-927.3mV  -54.74mA   -63.7mA    -67.06mA
-709.1mV  -32.79mA   -23.51mA   -42.31mA
-327.3mV  -7.277mA   -5.319mA   -8.518mA
1.909V    43.07mA    32.33mA    49.74mA
2.564V    104.4mA    85.88mA    122.4mA
2.836V    149.4mA    139.1mA    161.6mA
3V        193.1mA    196.1mA    201.9mA
3.545V    1.109A     1.701A     721.1mA
[Pullup]
|   voltage   I(typ)   I(min)   I(max)
-1.8V     1.383A     1.045A     2.063A
-1.691V   831.6mA    636.9mA    1.324A
-1.527V   357.1mA    291.9mA    550.1mA
-1.255V   166mA      118.4mA    227.2mA
2.509V    -41.64mA   -52.15mA   -32.21mA
2.673V    -57.5mA    -327.1mA   -50.99mA
2.836V    -112mA     -1.322A    -69.92mA
3V        -788.6mA   -2.656A    -101.4mA
3.055V    -1.19A     -3.13A     -133.6mA
3.164V    -2.091A    -4.103A    -481.4mA
3.273V    -3.057A    -5.094A    -1.275A
3.545V    -5.576A    -7.574A    -3.716A
[Ramp]
| variable   typ   min   max
dV/dt_f  0.2395137/0.2231039n  0.2299782/0.2699226n  0.2497253/0.1796404n
dV/dt_r  0.2664369/0.2353572n  0.2570285/0.3066133n  0.2800521/0.1906354n
R_load = 50
[Rising Waveform]
R_fixture = 50
V_fixture = 0.199083929070218
V_fixture_min = 0.191852772547157
V_fixture_max = 0.207685213126834
|   time   V(typ)   V(min)   V(max)
0s        96.56mV    110mV      93.16mV
325ps     96.56mV    110mV      95.04mV
391ps     98.57mV    110mV      137.7mV
485ps     145.6mV    112mV      202.4mV
518ps     179.5mV    128.2mV    241.5mV
586ps     201.9mV    147.2mV    298.8mV
640ps     232.4mV    172.5mV    319.7mV
748ps     293.2mV    208.7mV    331.8mV
886ps     306.5mV    259.5mV    329.8mV
1.024ns   307.9mV    272mV      324.1mV
[Falling Waveform]
R_fixture = 50
V_fixture = 0.199083929070218
V_fixture_min = 0.191852772547157
V_fixture_max = 0.207685213126834
|   time   V(typ)   V(min)   V(max)
0s        301.6mV    273.7mV    322.2mV
306ps     301.6mV    273.7mV    320mV
368ps     298.1mV    273.7mV    273.5mV
412ps     260.7mV    273.8mV    222.9mV
455ps     250.9mV    271.3mV    209.6mV
582ps     163.4mV    224.4mV    100.9mV
640ps     150.4mV    198.1mV    96.47mV
691ps     105.3mV    186.9mV    95.6mV
848ps     98.98mV    118.6mV    94.31mV
1.078ns   98.22mV    111.7mV    93.61mV
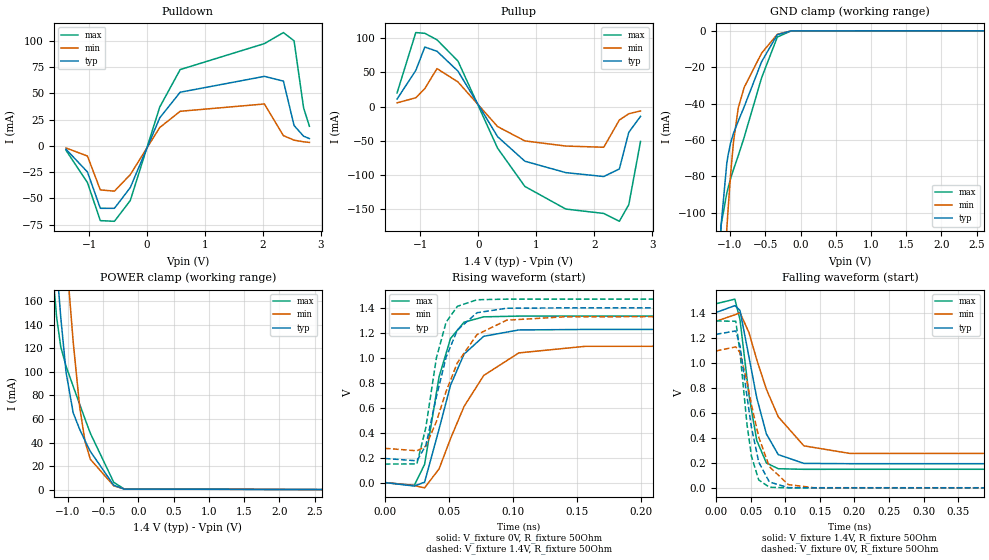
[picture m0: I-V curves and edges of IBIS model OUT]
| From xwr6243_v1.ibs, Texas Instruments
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|   Model OUT
[Model]   OUT
Model_type   3-state
Polarity   Non-Inverting
Vmeas = 0.7
Vref = 0
Cref = 2pF
Rref = 100000
|   typ   min   max
C_comp   0.972pF   0.950pF   0.976pF
| Where Nom  PVT is Nominal Process, 1.4V, 27C
|   Fast PVT is Strong Process,  1.47V, -40C
|   Slow PVT is Weak Process,   1.33V, 140C
[Voltage Range]   1.4   1.33   1.47
|Junction Temperature
[Temperature Range]   27   140   -40
[Pullup Reference]   1.4   1.33   1.47
[Pulldown Reference]   -0   0   0
[Power Clamp Reference]   1.4   1.33   1.47
[GND Clamp Reference]   0   0   0
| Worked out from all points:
|   slope of the pulldown table from 0 to 0.21 V, typ, clamps not added: 8.09 ohm
|   slope of the pullup table from 0 to 0.21 V, typ, clamps not added: 7.19 ohm
|   GND clamp passes 1 mA (typ) near -0.28 V on its own axis
|   POWER clamp passes 1 mA (typ) near -0.25 V on its own axis
|   falling waveform, V_fixture 1.4V, R_fixture 50Ohm: 20-80 % time 28.5ps typ, 44.8ps min, 19.8ps max; typ from 1.4 V to 0.193 V
|   rising waveform, V_fixture 0V, R_fixture 50Ohm: 20-80 % time 21.1ps typ, 32ps min, 14.7ps max; typ from 0 V to 1.23 V
|   rising waveform, V_fixture 1.4V, R_fixture 50Ohm: 20-80 % time 18.2ps typ, 25.9ps min, 13.5ps max; typ from 0.193 V to 1.4 V
|   falling waveform, V_fixture 0V, R_fixture 50Ohm: 20-80 % time 21.1ps typ, 29.1ps min, 15.9ps max; typ from 1.23 V to 0 V
[Pulldown]
|   Voltage   I(typ)   I(min)   I(max)
-1.4V     -3.224mA   -2.012mA   -4.211mA
-1.03V    -24.89mA   -9.71mA    -35mA
-807.8mV  -59.54mA   -42.01mA   -71.28mA
-564.2mV  -59.55mA   -43.16mA   -71.93mA
-291.2mV  -39.82mA   -27.45mA   -52.12mA
217mV     26.68mA    17.48mA    36.96mA
569.8mV   51.12mA    32.95mA    72.71mA
2.023V    66.23mA    39.92mA    97.47mA
2.351V    61.7mA     9.75mA     108mA
2.535V    19.4mA     5.413mA    100.1mA
2.699V    9.185mA    3.841mA    36.16mA
2.8V      6.936mA    3.28mA     18.62mA
[GND Clamp]
|   Voltage   I(typ)   I(min)   I(max)
-1.4V     -319.8mA   -391.4mA   -287.8mA
-1.127V   -106.9mA   -164.2mA   -106.7mA
-1.047V   -73.14mA   -109.6mA   -89.4mA
-1.03V    -68.83mA   -99.43mA   -86.67mA
-992.6mV  -61.69mA   -79.04mA   -81.28mA
-950.6mV  -56.26mA   -60.91mA   -76.16mA
-883.4mV  -49.64mA   -42.33mA   -68.62mA
-799.4mV  -41.72mA   -31.07mA   -58.51mA
-551.6mV  -16.93mA   -12.23mA   -25.73mA
-329mV    -2.108mA   -1.91mA    -3.401mA
-131.6mV  -28.42uA   -52.07uA   -32.06uA
2.8V      0A         0A         0A
[Pullup]
|   Voltage   I(typ)   I(min)   I(max)
-1.4V     11.14mA    5.586mA    20.09mA
-1.077V   52.96mA    13.02mA    108.4mA
-921.2mV  87.19mA    26.39mA    107.3mA
-711.2mV  81.1mA     55.67mA    97.83mA
-350mV    52.03mA    36.23mA    66.77mA
334.6mV   -43.92mA   -29.14mA   -60.77mA
805mV     -79.79mA   -50.09mA   -116.7mA
1.511V    -96.5mA    -57.62mA   -149.8mA
2.166V    -102.2mA   -59.38mA   -156.2mA
2.435V    -91.09mA   -19.54mA   -167.7mA
2.598V    -37.49mA   -10.35mA   -143.3mA
2.8V      -14.2mA    -6.262mA   -50.97mA
[POWER Clamp]
|   Voltage   I(typ)   I(min)   I(max)
-1.4V     400.4mA    529.2mA    337.6mA
-1.253V   269mA      395.5mA    211.4mA
-1.161V   191.7mA    313.9mA    146.9mA
-1.102V   146.9mA    263.5mA    121.5mA
-1.026V   99.58mA    201.3mA    104.8mA
-925.4mV  65.29mA    125.7mA    87.84mA
-833mV    51.23mA    70.17mA    72.51mA
-757.4mV  41.63mA    40.93mA    60.04mA
-681.8mV  32.49mA    25.81mA    47.9mA
-350mV    3.689mA    3.236mA    6.232mA
-203mV    464.8uA    538.7uA    608uA
2.8V      0A         0A         0A
[Ramp]
R_load = 50
|   typ   min   max
dV/dt_r   0.735857/2.10588e-11   0.655592/3.20085e-11   0.80005/1.47498e-11
dV/dt_f   0.724221/2.84906e-11   0.633384/4.48298e-11   0.793023/1.98344e-11
[Falling Waveform]
V_fixture = 1.4V
V_fixture_min = 1.33V
V_fixture_max = 1.47V
R_fixture = 50Ohm
C_fixture = 0F
|   Time   V(typ)   V(min)   V(max)
0s        1.4V       1.33V      1.47V
27.37ps   1.455V     1.382V     1.507V
34.76ps   1.417V     1.399V     1.342V
47.82ps   1.042V     1.238V     736.1mV
58.92ps   720.1mV    1.024V     378.7mV
72.91ps   430.2mV    787mV      198.6mV
89.98ps   265.6mV    567.8mV    152.6mV
127ps     195.2mV    335.5mV    147.9mV
193.5ps   192.8mV    274.8mV    148.3mV
2ns       193mV      274.4mV    148.3mV
[Rising Waveform]
V_fixture = 0V
V_fixture_min = 0V
V_fixture_max = 0V
R_fixture = 50Ohm
C_fixture = 0F
|   Time   V(typ)   V(min)   V(max)
0s        43.55uV    74.14uV    34.1uV
22.96ps   -27.92mV   -23.88mV   -22.7mV
31.02ps   2.969mV    -42.52mV   145.8mV
42.35ps   429.5mV    110.1mV    848.4mV
51.29ps   780.3mV    352.2mV    1.155V
61.83ps   1.029V     609.6mV    1.285V
77.19ps   1.172V     858mV      1.328V
104.6ps   1.223V     1.039V     1.334V
156.8ps   1.227V     1.092V     1.334V
2ns       1.226V     1.093V     1.333V
[Rising Waveform]
V_fixture = 1.4V
V_fixture_min = 1.33V
V_fixture_max = 1.47V
R_fixture = 50Ohm
C_fixture = 0F
|   Time   V(typ)   V(min)   V(max)
0s        193mV      274.4mV    148.3mV
25ps      174.4mV    254.6mV    149.4mV
31.96ps   295.8mV    291.5mV    438.8mV
40.17ps   684.7mV    486.9mV    995.9mV
47.82ps   1.005V     730.8mV    1.285V
56.6ps    1.222V     959.2mV    1.412V
71.95ps   1.361V     1.186V     1.465V
95.11ps   1.397V     1.301V     1.47V
141.5ps   1.4V       1.329V     1.47V
2ns       1.4V       1.33V      1.47V
[Falling Waveform]
|Gnd
V_fixture = 0V
V_fixture_min = 0V
V_fixture_max = 0V
R_fixture = 50Ohm
C_fixture = 0F
|   Time   V(typ)   V(min)   V(max)
0s        1.226V     1.093V     1.333V
28.68ps   1.253V     1.126V     1.33V
34.76ps   1.134V     1.08V      1.08V
44.86ps   729.8mV    847.1mV    506.7mV
51.29ps   483.4mV    664.7mV    251.8mV
61.83ps   204.7mV    405.1mV    63.27mV
77.19ps   46.79mV    168.9mV    4.809mV
104.6ps   1.475mV    25.67mV    -174.3uV
141.5ps   206.5uV    997.9uV    38.36uV
2ns       43.55uV    74.14uV    34.35uV
